VERSION 5.8 ;
BUSBITCHARS "[]" ;
DIVIDERCHAR "/" ;

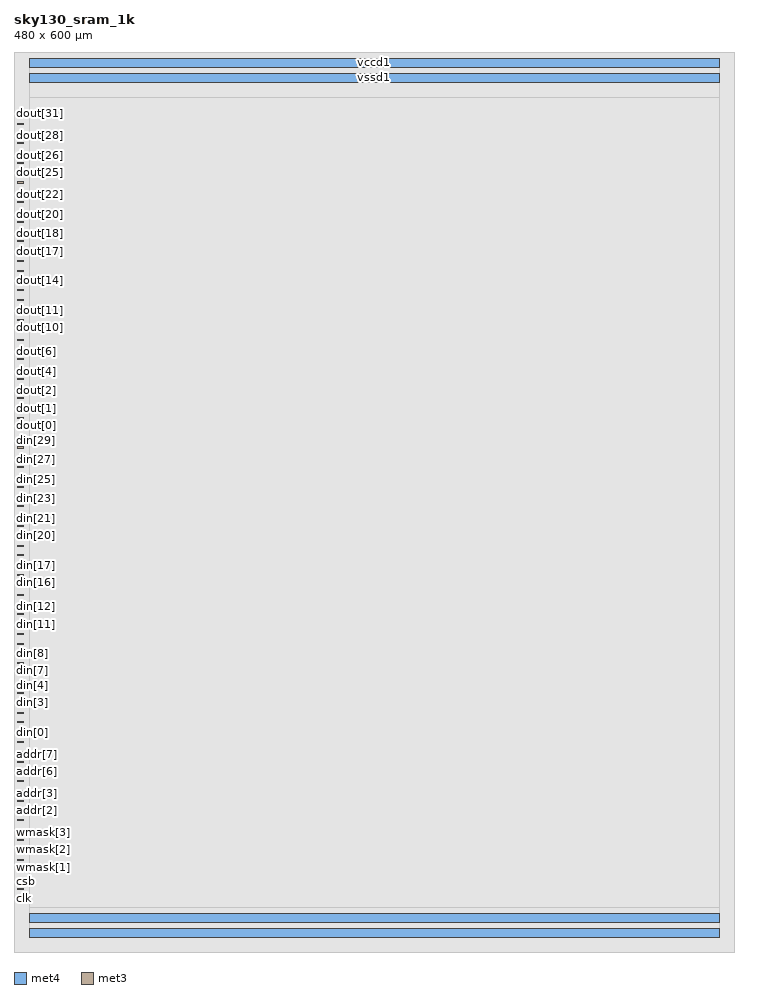
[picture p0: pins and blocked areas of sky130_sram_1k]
MACRO sky130_sram_1k
  CLASS BLOCK ;
  ORIGIN 0.000 0.000 ;
  FOREIGN sky130_sram_1k 0.000 0.000 ;
  SIZE 480.000 BY 600.000 ;
  SYMMETRY X Y ;
  PIN vccd1
    DIRECTION INOUT ;
    USE POWER ;
    PORT
      LAYER met4 ;
        RECT 10.000 590.000 470.000 596.000 ;
        RECT 10.000 10.000 470.000 16.000 ;
    END
  END vccd1
  PIN vssd1
    DIRECTION INOUT ;
    USE GROUND ;
    PORT
      LAYER met4 ;
        RECT 10.000 580.000 470.000 586.000 ;
        RECT 10.000 20.000 470.000 26.000 ;
    END
  END vssd1
  PIN clk
    DIRECTION INPUT ;
    USE SIGNAL ;
    PORT
      LAYER met3 ;
        RECT 2.000 35.000 6.500 35.680 ;
    END
  END clk
  PIN csb
    DIRECTION INPUT ;
    USE SIGNAL ;
    PORT
      LAYER met3 ;
        RECT 2.000 41.545 6.500 42.225 ;
    END
  END csb
  PIN web
    DIRECTION INPUT ;
    USE SIGNAL ;
    PORT
      LAYER met3 ;
        RECT 2.000 48.085 6.500 48.765 ;
    END
  END web
  PIN wmask[0]
    DIRECTION INPUT ;
    USE SIGNAL ;
    PORT
      LAYER met3 ;
        RECT 2.000 54.630 6.500 55.310 ;
    END
  END wmask[0]
  PIN wmask[1]
    DIRECTION INPUT ;
    USE SIGNAL ;
    PORT
      LAYER met3 ;
        RECT 2.000 61.175 6.500 61.855 ;
    END
  END wmask[1]
  PIN wmask[2]
    DIRECTION INPUT ;
    USE SIGNAL ;
    PORT
      LAYER met3 ;
        RECT 2.000 67.715 6.500 68.395 ;
    END
  END wmask[2]
  PIN wmask[3]
    DIRECTION INPUT ;
    USE SIGNAL ;
    PORT
      LAYER met3 ;
        RECT 2.000 74.260 6.500 74.940 ;
    END
  END wmask[3]
  PIN addr[0]
    DIRECTION INPUT ;
    USE SIGNAL ;
    PORT
      LAYER met3 ;
        RECT 2.000 80.800 6.500 81.480 ;
    END
  END addr[0]
  PIN addr[1]
    DIRECTION INPUT ;
    USE SIGNAL ;
    PORT
      LAYER met3 ;
        RECT 2.000 87.345 6.500 88.025 ;
    END
  END addr[1]
  PIN addr[2]
    DIRECTION INPUT ;
    USE SIGNAL ;
    PORT
      LAYER met3 ;
        RECT 2.000 93.890 6.500 94.570 ;
    END
  END addr[2]
  PIN addr[3]
    DIRECTION INPUT ;
    USE SIGNAL ;
    PORT
      LAYER met3 ;
        RECT 2.000 100.430 6.500 101.110 ;
    END
  END addr[3]
  PIN addr[4]
    DIRECTION INPUT ;
    USE SIGNAL ;
    PORT
      LAYER met3 ;
        RECT 2.000 106.975 6.500 107.655 ;
    END
  END addr[4]
  PIN addr[5]
    DIRECTION INPUT ;
    USE SIGNAL ;
    PORT
      LAYER met3 ;
        RECT 2.000 113.520 6.500 114.200 ;
    END
  END addr[5]
  PIN addr[6]
    DIRECTION INPUT ;
    USE SIGNAL ;
    PORT
      LAYER met3 ;
        RECT 2.000 120.060 6.500 120.740 ;
    END
  END addr[6]
  PIN addr[7]
    DIRECTION INPUT ;
    USE SIGNAL ;
    PORT
      LAYER met3 ;
        RECT 2.000 126.605 6.500 127.285 ;
    END
  END addr[7]
  PIN addr[8]
    DIRECTION INPUT ;
    USE SIGNAL ;
    PORT
      LAYER met3 ;
        RECT 2.000 133.150 6.500 133.830 ;
    END
  END addr[8]
  PIN addr[9]
    DIRECTION INPUT ;
    USE SIGNAL ;
    PORT
      LAYER met3 ;
        RECT 2.000 139.690 6.500 140.370 ;
    END
  END addr[9]
  PIN din[0]
    DIRECTION INPUT ;
    USE SIGNAL ;
    PORT
      LAYER met3 ;
        RECT 2.000 146.235 6.500 146.915 ;
    END
  END din[0]
  PIN din[1]
    DIRECTION INPUT ;
    USE SIGNAL ;
    PORT
      LAYER met3 ;
        RECT 2.000 152.780 6.500 153.460 ;
    END
  END din[1]
  PIN din[2]
    DIRECTION INPUT ;
    USE SIGNAL ;
    PORT
      LAYER met3 ;
        RECT 2.000 159.320 6.500 160.000 ;
    END
  END din[2]
  PIN din[3]
    DIRECTION INPUT ;
    USE SIGNAL ;
    PORT
      LAYER met3 ;
        RECT 2.000 165.865 6.500 166.545 ;
    END
  END din[3]
  PIN din[4]
    DIRECTION INPUT ;
    USE SIGNAL ;
    PORT
      LAYER met3 ;
        RECT 2.000 172.405 6.500 173.085 ;
    END
  END din[4]
  PIN din[5]
    DIRECTION INPUT ;
    USE SIGNAL ;
    PORT
      LAYER met3 ;
        RECT 2.000 178.950 6.500 179.630 ;
    END
  END din[5]
  PIN din[6]
    DIRECTION INPUT ;
    USE SIGNAL ;
    PORT
      LAYER met3 ;
        RECT 2.000 185.495 6.500 186.175 ;
    END
  END din[6]
  PIN din[7]
    DIRECTION INPUT ;
    USE SIGNAL ;
    PORT
      LAYER met3 ;
        RECT 2.000 192.035 6.500 192.715 ;
    END
  END din[7]
  PIN din[8]
    DIRECTION INPUT ;
    USE SIGNAL ;
    PORT
      LAYER met3 ;
        RECT 2.000 198.580 6.500 199.260 ;
    END
  END din[8]
  PIN din[9]
    DIRECTION INPUT ;
    USE SIGNAL ;
    PORT
      LAYER met3 ;
        RECT 2.000 205.125 6.500 205.805 ;
    END
  END din[9]
  PIN din[10]
    DIRECTION INPUT ;
    USE SIGNAL ;
    PORT
      LAYER met3 ;
        RECT 2.000 211.665 6.500 212.345 ;
    END
  END din[10]
  PIN din[11]
    DIRECTION INPUT ;
    USE SIGNAL ;
    PORT
      LAYER met3 ;
        RECT 2.000 218.210 6.500 218.890 ;
    END
  END din[11]
  PIN din[12]
    DIRECTION INPUT ;
    USE SIGNAL ;
    PORT
      LAYER met3 ;
        RECT 2.000 224.755 6.500 225.435 ;
    END
  END din[12]
  PIN din[13]
    DIRECTION INPUT ;
    USE SIGNAL ;
    PORT
      LAYER met3 ;
        RECT 2.000 231.295 6.500 231.975 ;
    END
  END din[13]
  PIN din[14]
    DIRECTION INPUT ;
    USE SIGNAL ;
    PORT
      LAYER met3 ;
        RECT 2.000 237.840 6.500 238.520 ;
    END
  END din[14]
  PIN din[15]
    DIRECTION INPUT ;
    USE SIGNAL ;
    PORT
      LAYER met3 ;
        RECT 2.000 244.385 6.500 245.065 ;
    END
  END din[15]
  PIN din[16]
    DIRECTION INPUT ;
    USE SIGNAL ;
    PORT
      LAYER met3 ;
        RECT 2.000 250.925 6.500 251.605 ;
    END
  END din[16]
  PIN din[17]
    DIRECTION INPUT ;
    USE SIGNAL ;
    PORT
      LAYER met3 ;
        RECT 2.000 257.470 6.500 258.150 ;
    END
  END din[17]
  PIN din[18]
    DIRECTION INPUT ;
    USE SIGNAL ;
    PORT
      LAYER met3 ;
        RECT 2.000 264.010 6.500 264.690 ;
    END
  END din[18]
  PIN din[19]
    DIRECTION INPUT ;
    USE SIGNAL ;
    PORT
      LAYER met3 ;
        RECT 2.000 270.555 6.500 271.235 ;
    END
  END din[19]
  PIN din[20]
    DIRECTION INPUT ;
    USE SIGNAL ;
    PORT
      LAYER met3 ;
        RECT 2.000 277.100 6.500 277.780 ;
    END
  END din[20]
  PIN din[21]
    DIRECTION INPUT ;
    USE SIGNAL ;
    PORT
      LAYER met3 ;
        RECT 2.000 283.640 6.500 284.320 ;
    END
  END din[21]
  PIN din[22]
    DIRECTION INPUT ;
    USE SIGNAL ;
    PORT
      LAYER met3 ;
        RECT 2.000 290.185 6.500 290.865 ;
    END
  END din[22]
  PIN din[23]
    DIRECTION INPUT ;
    USE SIGNAL ;
    PORT
      LAYER met3 ;
        RECT 2.000 296.730 6.500 297.410 ;
    END
  END din[23]
  PIN din[24]
    DIRECTION INPUT ;
    USE SIGNAL ;
    PORT
      LAYER met3 ;
        RECT 2.000 303.270 6.500 303.950 ;
    END
  END din[24]
  PIN din[25]
    DIRECTION INPUT ;
    USE SIGNAL ;
    PORT
      LAYER met3 ;
        RECT 2.000 309.815 6.500 310.495 ;
    END
  END din[25]
  PIN din[26]
    DIRECTION INPUT ;
    USE SIGNAL ;
    PORT
      LAYER met3 ;
        RECT 2.000 316.360 6.500 317.040 ;
    END
  END din[26]
  PIN din[27]
    DIRECTION INPUT ;
    USE SIGNAL ;
    PORT
      LAYER met3 ;
        RECT 2.000 322.900 6.500 323.580 ;
    END
  END din[27]
  PIN din[28]
    DIRECTION INPUT ;
    USE SIGNAL ;
    PORT
      LAYER met3 ;
        RECT 2.000 329.445 6.500 330.125 ;
    END
  END din[28]
  PIN din[29]
    DIRECTION INPUT ;
    USE SIGNAL ;
    PORT
      LAYER met3 ;
        RECT 2.000 335.990 6.500 336.670 ;
    END
  END din[29]
  PIN din[30]
    DIRECTION INPUT ;
    USE SIGNAL ;
    PORT
      LAYER met3 ;
        RECT 2.000 342.530 6.500 343.210 ;
    END
  END din[30]
  PIN din[31]
    DIRECTION INPUT ;
    USE SIGNAL ;
    PORT
      LAYER met3 ;
        RECT 2.000 349.075 6.500 349.755 ;
    END
  END din[31]
  PIN dout[0]
    DIRECTION OUTPUT ;
    USE SIGNAL ;
    PORT
      LAYER met3 ;
        RECT 2.000 355.615 6.500 356.295 ;
    END
  END dout[0]
  PIN dout[1]
    DIRECTION OUTPUT ;
    USE SIGNAL ;
    PORT
      LAYER met3 ;
        RECT 2.000 362.160 6.500 362.840 ;
    END
  END dout[1]
  PIN dout[2]
    DIRECTION OUTPUT ;
    USE SIGNAL ;
    PORT
      LAYER met3 ;
        RECT 2.000 368.705 6.500 369.385 ;
    END
  END dout[2]
  PIN dout[3]
    DIRECTION OUTPUT ;
    USE SIGNAL ;
    PORT
      LAYER met3 ;
        RECT 2.000 375.245 6.500 375.925 ;
    END
  END dout[3]
  PIN dout[4]
    DIRECTION OUTPUT ;
    USE SIGNAL ;
    PORT
      LAYER met3 ;
        RECT 2.000 381.790 6.500 382.470 ;
    END
  END dout[4]
  PIN dout[5]
    DIRECTION OUTPUT ;
    USE SIGNAL ;
    PORT
      LAYER met3 ;
        RECT 2.000 388.335 6.500 389.015 ;
    END
  END dout[5]
  PIN dout[6]
    DIRECTION OUTPUT ;
    USE SIGNAL ;
    PORT
      LAYER met3 ;
        RECT 2.000 394.875 6.500 395.555 ;
    END
  END dout[6]
  PIN dout[7]
    DIRECTION OUTPUT ;
    USE SIGNAL ;
    PORT
      LAYER met3 ;
        RECT 2.000 401.420 6.500 402.100 ;
    END
  END dout[7]
  PIN dout[8]
    DIRECTION OUTPUT ;
    USE SIGNAL ;
    PORT
      LAYER met3 ;
        RECT 2.000 407.965 6.500 408.645 ;
    END
  END dout[8]
  PIN dout[9]
    DIRECTION OUTPUT ;
    USE SIGNAL ;
    PORT
      LAYER met3 ;
        RECT 2.000 414.505 6.500 415.185 ;
    END
  END dout[9]
  PIN dout[10]
    DIRECTION OUTPUT ;
    USE SIGNAL ;
    PORT
      LAYER met3 ;
        RECT 2.000 421.050 6.500 421.730 ;
    END
  END dout[10]
  PIN dout[11]
    DIRECTION OUTPUT ;
    USE SIGNAL ;
    PORT
      LAYER met3 ;
        RECT 2.000 427.595 6.500 428.275 ;
    END
  END dout[11]
  PIN dout[12]
    DIRECTION OUTPUT ;
    USE SIGNAL ;
    PORT
      LAYER met3 ;
        RECT 2.000 434.135 6.500 434.815 ;
    END
  END dout[12]
  PIN dout[13]
    DIRECTION OUTPUT ;
    USE SIGNAL ;
    PORT
      LAYER met3 ;
        RECT 2.000 440.680 6.500 441.360 ;
    END
  END dout[13]
  PIN dout[14]
    DIRECTION OUTPUT ;
    USE SIGNAL ;
    PORT
      LAYER met3 ;
        RECT 2.000 447.220 6.500 447.900 ;
    END
  END dout[14]
  PIN dout[15]
    DIRECTION OUTPUT ;
    USE SIGNAL ;
    PORT
      LAYER met3 ;
        RECT 2.000 453.765 6.500 454.445 ;
    END
  END dout[15]
  PIN dout[16]
    DIRECTION OUTPUT ;
    USE SIGNAL ;
    PORT
      LAYER met3 ;
        RECT 2.000 460.310 6.500 460.990 ;
    END
  END dout[16]
  PIN dout[17]
    DIRECTION OUTPUT ;
    USE SIGNAL ;
    PORT
      LAYER met3 ;
        RECT 2.000 466.850 6.500 467.530 ;
    END
  END dout[17]
  PIN dout[18]
    DIRECTION OUTPUT ;
    USE SIGNAL ;
    PORT
      LAYER met3 ;
        RECT 2.000 473.395 6.500 474.075 ;
    END
  END dout[18]
  PIN dout[19]
    DIRECTION OUTPUT ;
    USE SIGNAL ;
    PORT
      LAYER met3 ;
        RECT 2.000 479.940 6.500 480.620 ;
    END
  END dout[19]
  PIN dout[20]
    DIRECTION OUTPUT ;
    USE SIGNAL ;
    PORT
      LAYER met3 ;
        RECT 2.000 486.480 6.500 487.160 ;
    END
  END dout[20]
  PIN dout[21]
    DIRECTION OUTPUT ;
    USE SIGNAL ;
    PORT
      LAYER met3 ;
        RECT 2.000 493.025 6.500 493.705 ;
    END
  END dout[21]
  PIN dout[22]
    DIRECTION OUTPUT ;
    USE SIGNAL ;
    PORT
      LAYER met3 ;
        RECT 2.000 499.570 6.500 500.250 ;
    END
  END dout[22]
  PIN dout[23]
    DIRECTION OUTPUT ;
    USE SIGNAL ;
    PORT
      LAYER met3 ;
        RECT 2.000 506.110 6.500 506.790 ;
    END
  END dout[23]
  PIN dout[24]
    DIRECTION OUTPUT ;
    USE SIGNAL ;
    PORT
      LAYER met3 ;
        RECT 2.000 512.655 6.500 513.335 ;
    END
  END dout[24]
  PIN dout[25]
    DIRECTION OUTPUT ;
    USE SIGNAL ;
    PORT
      LAYER met3 ;
        RECT 2.000 519.200 6.500 519.880 ;
    END
  END dout[25]
  PIN dout[26]
    DIRECTION OUTPUT ;
    USE SIGNAL ;
    PORT
      LAYER met3 ;
        RECT 2.000 525.740 6.500 526.420 ;
    END
  END dout[26]
  PIN dout[27]
    DIRECTION OUTPUT ;
    USE SIGNAL ;
    PORT
      LAYER met3 ;
        RECT 2.000 532.285 6.500 532.965 ;
    END
  END dout[27]
  PIN dout[28]
    DIRECTION OUTPUT ;
    USE SIGNAL ;
    PORT
      LAYER met3 ;
        RECT 2.000 538.825 6.500 539.505 ;
    END
  END dout[28]
  PIN dout[29]
    DIRECTION OUTPUT ;
    USE SIGNAL ;
    PORT
      LAYER met3 ;
        RECT 2.000 545.370 6.500 546.050 ;
    END
  END dout[29]
  PIN dout[30]
    DIRECTION OUTPUT ;
    USE SIGNAL ;
    PORT
      LAYER met3 ;
        RECT 2.000 551.915 6.500 552.595 ;
    END
  END dout[30]
  PIN dout[31]
    DIRECTION OUTPUT ;
    USE SIGNAL ;
    PORT
      LAYER met3 ;
        RECT 2.000 558.455 6.500 559.135 ;
    END
  END dout[31]
  OBS
    LAYER met1 ;
        RECT 0.000 0.000 480.000 600.000 ;
    LAYER met2 ;
        RECT 0.000 0.000 480.000 600.000 ;
    LAYER met3 ;
        RECT 10.000 10.000 470.000 590.000 ;
    LAYER met4 ;
        RECT 10.000 30.000 470.000 570.000 ;
  END
END sky130_sram_1k
END LIBRARY
